One B-rep face of a CAD part: STEP entity #1129.
In plain terms, the planar face has unit normal (1, 0, 0).
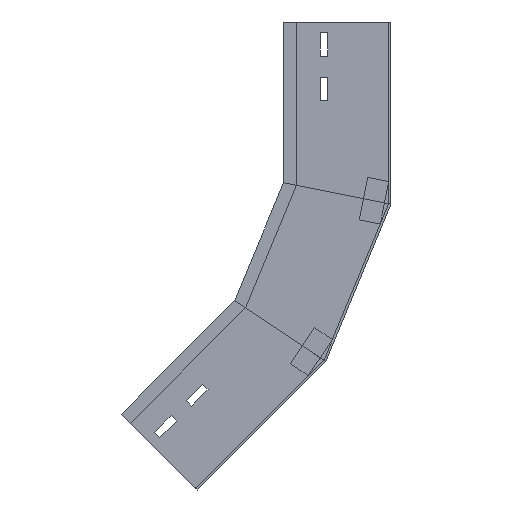
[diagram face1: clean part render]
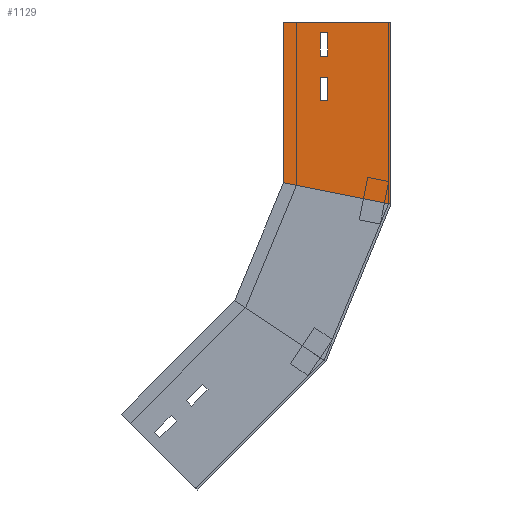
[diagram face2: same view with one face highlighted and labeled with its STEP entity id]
Its self-contained STEP definition (entity closure, numbers rounded to 3 decimals):
#3 = ORIENTED_EDGE ( 'NONE', *, *, #1090, .T. ) ;
#15 = ORIENTED_EDGE ( 'NONE', *, *, #1436, .F. ) ;
#35 = ORIENTED_EDGE ( 'NONE', *, *, #1209, .F. ) ;
#63 = ORIENTED_EDGE ( 'NONE', *, *, #745, .F. ) ;
#78 = CARTESIAN_POINT ( 'NONE',  ( 0., 215.346, -387.287 ) ) ;
#113 = VECTOR ( 'NONE', #606, 1000. ) ;
#119 = EDGE_LOOP ( 'NONE', ( #15, #63, #35, #1215 ) ) ;
#133 = LINE ( 'NONE', #597, #113 ) ;
#161 = CARTESIAN_POINT ( 'NONE',  ( 0., 190.83, -352.872 ) ) ;
#188 = CARTESIAN_POINT ( 'NONE',  ( 0., 220.295, -382.337 ) ) ;
#190 = ORIENTED_EDGE ( 'NONE', *, *, #914, .F. ) ;
#198 = VERTEX_POINT ( 'NONE', #1304 ) ;
#207 = EDGE_CURVE ( 'NONE', #559, #1024, #1097, .T. ) ;
#229 = ORIENTED_EDGE ( 'NONE', *, *, #1309, .F. ) ;
#239 = VECTOR ( 'NONE', #617, 1000. ) ;
#250 = ORIENTED_EDGE ( 'NONE', *, *, #1119, .T. ) ;
#264 = LINE ( 'NONE', #372, #875 ) ;
#274 = CARTESIAN_POINT ( 'NONE',  ( 0., 180.581, -435.96 ) ) ;
#300 = CARTESIAN_POINT ( 'NONE',  ( 0., 204.739, -366.78 ) ) ;
#305 = CARTESIAN_POINT ( 'NONE',  ( 0., 220.295, -382.337 ) ) ;
#309 = VERTEX_POINT ( 'NONE', #188 ) ;
#326 = CARTESIAN_POINT ( 'NONE',  ( 0., 60.655, -316.035 ) ) ;
#336 = EDGE_LOOP ( 'NONE', ( #250, #3, #1491, #400 ) ) ;
#372 = CARTESIAN_POINT ( 'NONE',  ( 0., 175.274, -337.315 ) ) ;
#373 = VECTOR ( 'NONE', #1098, 1000. ) ;
#383 = VECTOR ( 'NONE', #1076, 1000. ) ;
#396 = VERTEX_POINT ( 'NONE', #1247 ) ;
#400 = ORIENTED_EDGE ( 'NONE', *, *, #1207, .F. ) ;
#402 = CARTESIAN_POINT ( 'NONE',  ( 0., 220.295, -382.337 ) ) ;
#406 = EDGE_LOOP ( 'NONE', ( #1401, #621, #190, #229 ) ) ;
#427 = VERTEX_POINT ( 'NONE', #464 ) ;
#446 = VECTOR ( 'NONE', #776, 1000. ) ;
#447 = VERTEX_POINT ( 'NONE', #1268 ) ;
#448 = CARTESIAN_POINT ( 'NONE',  ( 0., 131.366, -245.324 ) ) ;
#464 = CARTESIAN_POINT ( 'NONE',  ( 0., 185.88, -357.821 ) ) ;
#466 = VERTEX_POINT ( 'NONE', #699 ) ;
#559 = VERTEX_POINT ( 'NONE', #1056 ) ;
#586 = CARTESIAN_POINT ( 'NONE',  ( 0., 145.431, -259.389 ) ) ;
#597 = CARTESIAN_POINT ( 'NONE',  ( 0., 185.88, -357.821 ) ) ;
#603 = VECTOR ( 'NONE', #1250, 1000. ) ;
#606 = DIRECTION ( 'NONE',  ( 0., 0.707, -0.707 ) ) ;
#617 = DIRECTION ( 'NONE',  ( 0., -0.707, 0.707 ) ) ;
#621 = ORIENTED_EDGE ( 'NONE', *, *, #1008, .F. ) ;
#629 = CARTESIAN_POINT ( 'NONE',  ( 0., 60.655, -316.035 ) ) ;
#655 = AXIS2_PLACEMENT_3D ( 'NONE', #326, #670, #1334 ) ;
#667 = CARTESIAN_POINT ( 'NONE',  ( 0., 86.366, -298.856 ) ) ;
#670 = DIRECTION ( 'NONE',  ( -1., 0., 0. ) ) ;
#671 = LINE ( 'NONE', #305, #446 ) ;
#678 = EDGE_CURVE ( 'NONE', #447, #1185, #862, .T. ) ;
#680 = CARTESIAN_POINT ( 'NONE',  ( 0., 170.324, -342.265 ) ) ;
#699 = CARTESIAN_POINT ( 'NONE',  ( 0., 60.655, -316.035 ) ) ;
#731 = DIRECTION ( 'NONE',  ( 0., 0.707, 0.707 ) ) ;
#745 = EDGE_CURVE ( 'NONE', #198, #309, #671, .T. ) ;
#775 = FACE_BOUND ( 'NONE', #406, .T. ) ;
#776 = DIRECTION ( 'NONE',  ( 0., 0.707, 0.707 ) ) ;
#799 = CARTESIAN_POINT ( 'NONE',  ( 0., 204.739, -366.78 ) ) ;
#862 = LINE ( 'NONE', #1330, #239 ) ;
#875 = VECTOR ( 'NONE', #1032, 1000. ) ;
#888 = CARTESIAN_POINT ( 'NONE',  ( 0., 175.274, -337.315 ) ) ;
#909 = LINE ( 'NONE', #799, #603 ) ;
#914 = EDGE_CURVE ( 'NONE', #954, #427, #133, .T. ) ;
#954 = VERTEX_POINT ( 'NONE', #680 ) ;
#962 = EDGE_CURVE ( 'NONE', #1396, #396, #909, .T. ) ;
#974 = LINE ( 'NONE', #629, #383 ) ;
#980 = VECTOR ( 'NONE', #1308, 1000. ) ;
#983 = DIRECTION ( 'NONE',  ( 0., 0.707, -0.707 ) ) ;
#991 = FACE_OUTER_BOUND ( 'NONE', #336, .T. ) ;
#1008 = EDGE_CURVE ( 'NONE', #427, #447, #1398, .T. ) ;
#1024 = VERTEX_POINT ( 'NONE', #1440 ) ;
#1032 = DIRECTION ( 'NONE',  ( 0., -0.707, -0.707 ) ) ;
#1056 = CARTESIAN_POINT ( 'NONE',  ( 0., 180.581, -435.96 ) ) ;
#1076 = DIRECTION ( 'NONE',  ( 0., 0.707, -0.707 ) ) ;
#1090 = EDGE_CURVE ( 'NONE', #466, #559, #974, .T. ) ;
#1097 = LINE ( 'NONE', #274, #1368 ) ;
#1098 = DIRECTION ( 'NONE',  ( 0., -0.707, 0.707 ) ) ;
#1109 = DIRECTION ( 'NONE',  ( 0., 0.707, -0.707 ) ) ;
#1115 = FACE_BOUND ( 'NONE', #119, .T. ) ;
#1119 = EDGE_CURVE ( 'NONE', #1294, #466, #1253, .T. ) ;
#1122 = LINE ( 'NONE', #78, #1135 ) ;
#1129 = ADVANCED_FACE ( 'NONE', ( #1115, #775, #991 ), #1458, .F. ) ;
#1135 = VECTOR ( 'NONE', #983, 1000. ) ;
#1185 = VERTEX_POINT ( 'NONE', #888 ) ;
#1207 = EDGE_CURVE ( 'NONE', #1294, #1024, #1349, .T. ) ;
#1209 = EDGE_CURVE ( 'NONE', #396, #198, #1122, .T. ) ;
#1215 = ORIENTED_EDGE ( 'NONE', *, *, #962, .F. ) ;
#1220 = VECTOR ( 'NONE', #1109, 1000. ) ;
#1222 = DIRECTION ( 'NONE',  ( 0., -0.831, -0.556 ) ) ;
#1247 = CARTESIAN_POINT ( 'NONE',  ( 0., 199.789, -371.73 ) ) ;
#1250 = DIRECTION ( 'NONE',  ( 0., -0.707, -0.707 ) ) ;
#1253 = LINE ( 'NONE', #667, #1339 ) ;
#1268 = CARTESIAN_POINT ( 'NONE',  ( 0., 190.83, -352.872 ) ) ;
#1294 = VERTEX_POINT ( 'NONE', #586 ) ;
#1304 = CARTESIAN_POINT ( 'NONE',  ( 0., 215.346, -387.287 ) ) ;
#1308 = DIRECTION ( 'NONE',  ( 0., 0.707, 0.707 ) ) ;
#1309 = EDGE_CURVE ( 'NONE', #1185, #954, #264, .T. ) ;
#1330 = CARTESIAN_POINT ( 'NONE',  ( 0., 190.83, -352.872 ) ) ;
#1334 = DIRECTION ( 'NONE',  ( 0., 0., 1. ) ) ;
#1339 = VECTOR ( 'NONE', #1222, 1000. ) ;
#1349 = LINE ( 'NONE', #448, #1220 ) ;
#1368 = VECTOR ( 'NONE', #731, 1000. ) ;
#1396 = VERTEX_POINT ( 'NONE', #300 ) ;
#1398 = LINE ( 'NONE', #161, #980 ) ;
#1401 = ORIENTED_EDGE ( 'NONE', *, *, #678, .F. ) ;
#1436 = EDGE_CURVE ( 'NONE', #309, #1396, #1461, .T. ) ;
#1440 = CARTESIAN_POINT ( 'NONE',  ( 0., 251.291, -365.25 ) ) ;
#1458 = PLANE ( 'NONE',  #655 ) ;
#1461 = LINE ( 'NONE', #402, #373 ) ;
#1491 = ORIENTED_EDGE ( 'NONE', *, *, #207, .T. ) ;
